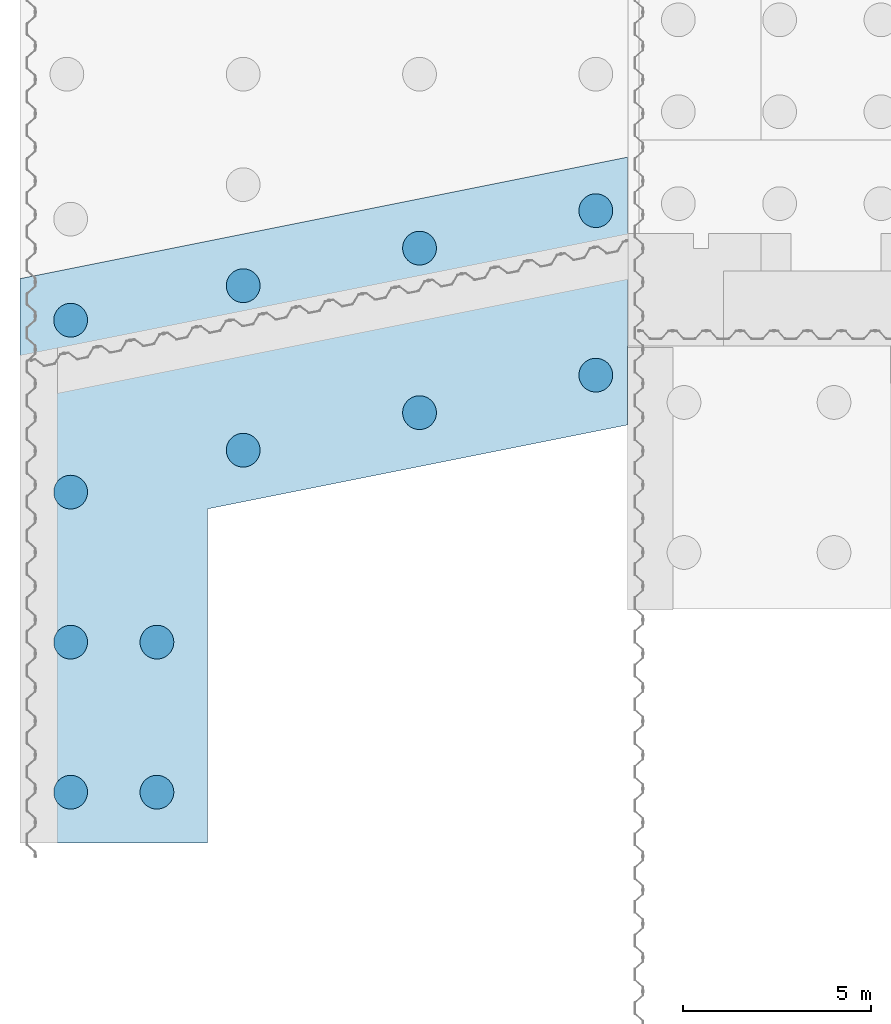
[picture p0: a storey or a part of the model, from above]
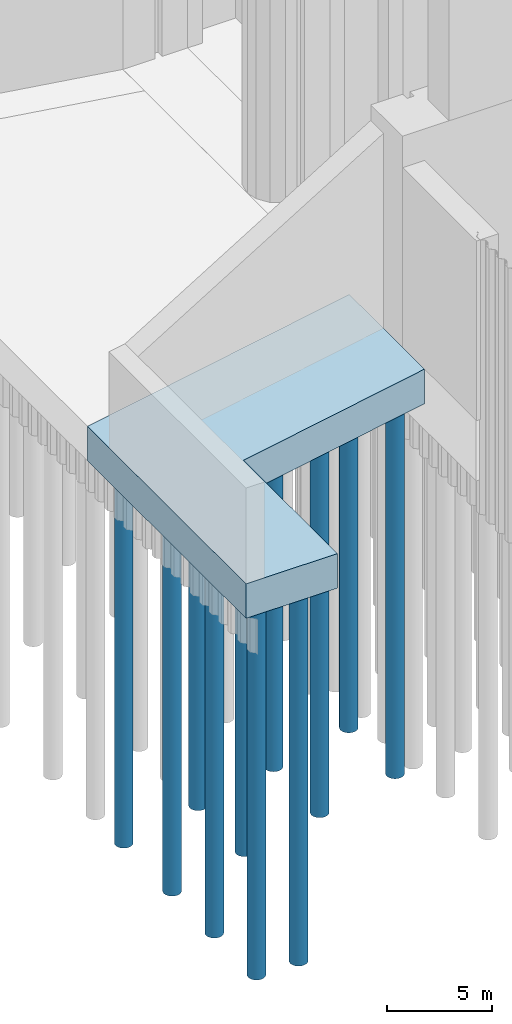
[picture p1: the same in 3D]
Properties of the parts of a building model (IFC2X3)

# File
Description: ViewDefinition [CoordinationView_V2.0]
File name: プロジェクト番号
Time: 2021-06-24T20:11:10
Written by: The EXPRESS Data Manager Version 5.02.0100.07 : 28 Aug 2013
Made in: 20210420_1515(x64) - Exporter 20.2.40.65 - 代替 UI 20.2.40.65
Comment: STEP Physical File produced by: The EXPRESS Data Manager Version 5.02.0100.07 : 28 Aug 2013 * Module: EDMstepFileFactory/EDMstandAlone * Creation date: Thu Jun 24 20:11:10 2021 * Host: A7687-TADA8 * Database: C:\Users\a9056\AppData\Local\Temp\2ef45a50-3783-4896-809c-960f0bd549e2\3312b9ed-52c4-4e0d-9066-fb21aae68b51\ifc * Database version: 5507 * Database creation date: Thu Jun 24 20:11:02 2021 * Schema: IFC2X3 * Model: DataRepository.ifc * Model creation date: Thu Jun 24 20:11:02 2021 * Header model: DataRepository.ifc_HeaderModel * Header model creation date: Thu Jun 24 20:11:02 2021 * EDMuser: sdai-user * EDMgroup: sdai-group * License ID and type: 5605 : Permanent license. Expiry date: * EDMstepFileFactory options: 020000

# IfcProject, プロジェクト番号
LongName: プロジェクト名; Phase: プロジェクト ステータス

# IfcSite, Default
RefLatitude: 35, 41, 6, 4943; RefLongitude: 139, 45, 3, 625488; RefElevation: 0 mm

# IfcBuilding
Pset_BuildingCommon - NumberOfStoreys: 1

# IfcBuildingStorey: レベル:レベル記号 - 基準, 設計GL
LongName: 設計GL; Elevation: 0 mm

# IfcSlab: 40001_Co_底版, 40001_Co_底版:40001_Co_底版:313550
In: 設計GL
Type - PredefinedType: FLOOR; Material: コンクリート - 現場打ちコンクリート
Type - Pset_QuantityTakeOff - Reference: 40001_Co_底版
Type - Pset_ReinforcementBarPitchOfSlab - Reference: 40001_Co_底版
Type - Pset_SlabCommon - Reference: 40001_Co_底版; IsExternal: no
Pset_QuantityTakeOff - sets with these values: 2
Pset_SlabCommon - PitchAngle: 0 deg

# IfcSlab: 40101_Co_川表胸壁(下流)底版, 40101_Co_川表胸壁(下流)底版:40101_Co_川表胸壁(下流)底版:313560
In: 設計GL
Type - PredefinedType: FLOOR; Material: コンクリート - 現場打ちコンクリート
Type - Pset_QuantityTakeOff - Reference: 40101_Co_川表胸壁(下流)底版
Type - Pset_ReinforcementBarPitchOfSlab - Reference: 40101_Co_川表胸壁(下流)底版
Type - Pset_SlabCommon - IsExternal: no; Reference: 40101_Co_川表胸壁(下流)底版
Pset_QuantityTakeOff - sets with these values: 2
Pset_SlabCommon - PitchAngle: 0 deg

# IfcSlab: 40201_Co_川表胸壁(上流)底版, 40201_Co_川表胸壁(上流)底版:40201_Co_川表胸壁(上流)底版:332443
In: 設計GL
Type - PredefinedType: FLOOR; Material: コンクリート - 現場打ちコンクリート
Type - Pset_QuantityTakeOff - Reference: 40201_Co_川表胸壁(上流)底版
Type - Pset_ReinforcementBarPitchOfSlab - Reference: 40201_Co_川表胸壁(上流)底版
Type - Pset_SlabCommon - IsExternal: no; Reference: 40201_Co_川表胸壁(上流)底版
Pset_QuantityTakeOff - sets with these values: 2
Pset_SlabCommon - PitchAngle: 0 deg

# IfcSlab: 40301_Co_川裏胸壁(下流)底版, 40301_Co_川裏胸壁(下流)底版:40301_Co_川裏胸壁(下流)底版:332453
In: 設計GL
Type - PredefinedType: FLOOR; Material: コンクリート - 現場打ちコンクリート
Type - Pset_QuantityTakeOff - Reference: 40301_Co_川裏胸壁(下流)底版
Type - Pset_ReinforcementBarPitchOfSlab - Reference: 40301_Co_川裏胸壁(下流)底版
Type - Pset_SlabCommon - IsExternal: no; Reference: 40301_Co_川裏胸壁(下流)底版
Pset_QuantityTakeOff - sets with these values: 2
Pset_SlabCommon - PitchAngle: 0 deg

# IfcSlab: 40401_Co_川裏胸壁(上流)底版, 40401_Co_川裏胸壁(上流)底版:40401_Co_川裏胸壁(上流)底版:332463
In: 設計GL
Type - PredefinedType: FLOOR; Material: コンクリート - 現場打ちコンクリート
Type - Pset_QuantityTakeOff - Reference: 40401_Co_川裏胸壁(上流)底版
Type - Pset_ReinforcementBarPitchOfSlab - Reference: 40401_Co_川裏胸壁(上流)底版
Type - Pset_SlabCommon - IsExternal: no; Reference: 40401_Co_川裏胸壁(上流)底版
Pset_QuantityTakeOff - sets with these values: 2
Pset_SlabCommon - PitchAngle: 0 deg

# IfcSlab: 40501_Co_川表翼壁(下流)底版, 40501_Co_川表翼壁(下流)底版:40501_Co_川表翼壁(下流)底版:332473
In: 設計GL
Type - PredefinedType: FLOOR; Material: コンクリート - 現場打ちコンクリート
Type - Pset_QuantityTakeOff - Reference: 40501_Co_川表翼壁(下流)底版
Type - Pset_ReinforcementBarPitchOfSlab - Reference: 40501_Co_川表翼壁(下流)底版
Type - Pset_SlabCommon - IsExternal: no; Reference: 40501_Co_川表翼壁(下流)底版
Pset_QuantityTakeOff - sets with these values: 2
Pset_SlabCommon - PitchAngle: 0 deg

# IfcSlab: 40601_Co_川表翼壁(上流)底版, 40601_Co_川表翼壁(上流)底版:40601_Co_川表翼壁(上流)底版:332483
In: 設計GL
Type - PredefinedType: FLOOR; Material: コンクリート - 現場打ちコンクリート
Type - Pset_QuantityTakeOff - Reference: 40601_Co_川表翼壁(上流)底版
Type - Pset_ReinforcementBarPitchOfSlab - Reference: 40601_Co_川表翼壁(上流)底版
Type - Pset_SlabCommon - IsExternal: no; Reference: 40601_Co_川表翼壁(上流)底版
Pset_QuantityTakeOff - sets with these values: 2
Pset_SlabCommon - PitchAngle: 0 deg

# IfcSlab: 40701_Co_川裏翼壁(下流)底版, 40701_Co_川裏翼壁(下流)底版:40701_Co_川裏翼壁(下流)底版:332493
In: 設計GL
Type - PredefinedType: FLOOR; Material: コンクリート - 現場打ちコンクリート
Type - Pset_QuantityTakeOff - Reference: 40701_Co_川裏翼壁(下流)底版
Type - Pset_ReinforcementBarPitchOfSlab - Reference: 40701_Co_川裏翼壁(下流)底版
Type - Pset_SlabCommon - IsExternal: no; Reference: 40701_Co_川裏翼壁(下流)底版
Pset_QuantityTakeOff - sets with these values: 2
Pset_SlabCommon - PitchAngle: 0 deg

# IfcSlab: 40801_Co_川裏翼壁(上流)底版 (3)
In: 設計GL
Type - PredefinedType: FLOOR; Material: コンクリート - 現場打ちコンクリート
Type - Pset_QuantityTakeOff - Reference: 40801_Co_川裏翼壁(上流)底版
Type - Pset_ReinforcementBarPitchOfSlab - Reference: 40801_Co_川裏翼壁(上流)底版
Type - Pset_SlabCommon - IsExternal: no; Reference: 40801_Co_川裏翼壁(上流)底版
Pset_QuantityTakeOff - sets with these values: 2
Pset_SlabCommon - PitchAngle: 0 deg
Name (40801_Co_川裏翼壁(上流)底版:40801_Co_川裏翼壁(上流)底版:...)
332503
332782
333462

# IfcSlab: 40901_Co_川表翼壁_底版, 40901_Co_川表翼壁_底版:40901_Co_川表翼壁_底版:332513
In: 設計GL
Type - PredefinedType: FLOOR; Material: コンクリート - 現場打ちコンクリート
Type - Pset_QuantityTakeOff - Reference: 40901_Co_川表翼壁_底版
Type - Pset_ReinforcementBarPitchOfSlab - Reference: 40901_Co_川表翼壁_底版
Type - Pset_SlabCommon - IsExternal: no; Reference: 40901_Co_川表翼壁_底版
Pset_QuantityTakeOff - sets with these values: 2
Pset_SlabCommon - PitchAngle: 0 deg

# IfcSlab: 41001_Co_川裏翼壁_底版, 41001_Co_川裏翼壁_底版:41001_Co_川裏翼壁_底版:332523
In: 設計GL
Type - PredefinedType: FLOOR; Material: コンクリート - 現場打ちコンクリート
Type - Pset_QuantityTakeOff - Reference: 41001_Co_川裏翼壁_底版
Type - Pset_ReinforcementBarPitchOfSlab - Reference: 41001_Co_川裏翼壁_底版
Type - Pset_SlabCommon - IsExternal: no; Reference: 41001_Co_川裏翼壁_底版
Pset_QuantityTakeOff - sets with these values: 2
Pset_SlabCommon - PitchAngle: 0 deg

# IfcSlab: 41101_Co_端堰柱(下流), 41101_Co_端堰柱(下流):41101_Co_端堰柱(下流):332533
In: 設計GL
Type - PredefinedType: FLOOR; Material: コンクリート - 現場打ちコンクリート
Type - Pset_QuantityTakeOff - Reference: 41101_Co_端堰柱(下流)
Type - Pset_ReinforcementBarPitchOfSlab - Reference: 41101_Co_端堰柱(下流)
Type - Pset_SlabCommon - IsExternal: no; Reference: 41101_Co_端堰柱(下流)
Pset_QuantityTakeOff - sets with these values: 2
Pset_SlabCommon - PitchAngle: 0 deg

# IfcSlab: 41201_Co_中央堰柱, 41201_Co_中央堰柱:41201_Co_中央堰柱:332543
In: 設計GL
Type - PredefinedType: FLOOR; Material: コンクリート - 現場打ちコンクリート
Type - Pset_QuantityTakeOff - Reference: 41201_Co_中央堰柱
Type - Pset_ReinforcementBarPitchOfSlab - Reference: 41201_Co_中央堰柱
Type - Pset_SlabCommon - IsExternal: no; Reference: 41201_Co_中央堰柱
Pset_QuantityTakeOff - sets with these values: 2
Pset_SlabCommon - PitchAngle: 0 deg

# IfcSlab: 41301_Co_端堰柱(上流), 41301_Co_端堰柱(上流):41301_Co_端堰柱(上流):332553
In: 設計GL
Type - PredefinedType: FLOOR; Material: コンクリート - 現場打ちコンクリート
Type - Pset_QuantityTakeOff - Reference: 41301_Co_端堰柱(上流)
Type - Pset_ReinforcementBarPitchOfSlab - Reference: 41301_Co_端堰柱(上流)
Type - Pset_SlabCommon - IsExternal: no; Reference: 41301_Co_端堰柱(上流)
Pset_QuantityTakeOff - sets with these values: 2
Pset_SlabCommon - PitchAngle: 0 deg

# IfcSlab: 41401_Co_川表胸壁(下流)側壁, 41401_Co_川表胸壁(下流)側壁:41401_Co_川表胸壁(下流)側壁:332563
In: 設計GL
Type - PredefinedType: FLOOR; Material: コンクリート - 現場打ちコンクリート
Type - Pset_QuantityTakeOff - Reference: 41401_Co_川表胸壁(下流)側壁
Type - Pset_ReinforcementBarPitchOfSlab - Reference: 41401_Co_川表胸壁(下流)側壁
Type - Pset_SlabCommon - IsExternal: no; Reference: 41401_Co_川表胸壁(下流)側壁
Pset_QuantityTakeOff - sets with these values: 2
Pset_SlabCommon - PitchAngle: 0 deg

# IfcSlab: 41501_Co_川表胸壁(上流)側壁, 41501_Co_川表胸壁(上流)側壁:41501_Co_川表胸壁(上流)側壁:332573
In: 設計GL
Type - PredefinedType: FLOOR; Material: コンクリート - 現場打ちコンクリート
Type - Pset_QuantityTakeOff - Reference: 41501_Co_川表胸壁(上流)側壁
Type - Pset_ReinforcementBarPitchOfSlab - Reference: 41501_Co_川表胸壁(上流)側壁
Type - Pset_SlabCommon - IsExternal: no; Reference: 41501_Co_川表胸壁(上流)側壁
Pset_QuantityTakeOff - sets with these values: 2
Pset_SlabCommon - PitchAngle: 0 deg

# IfcSlab: 41601_Co_川裏胸壁(下流)側壁, 41601_Co_川裏胸壁(下流)側壁:41601_Co_川裏胸壁(下流)側壁:332583
In: 設計GL
Type - PredefinedType: FLOOR; Material: コンクリート - 現場打ちコンクリート
Type - Pset_QuantityTakeOff - Reference: 41601_Co_川裏胸壁(下流)側壁
Type - Pset_ReinforcementBarPitchOfSlab - Reference: 41601_Co_川裏胸壁(下流)側壁
Type - Pset_SlabCommon - IsExternal: no; Reference: 41601_Co_川裏胸壁(下流)側壁
Pset_QuantityTakeOff - sets with these values: 2
Pset_SlabCommon - PitchAngle: 0 deg

# IfcSlab: 41701_Co_川裏胸壁(上流)側壁, 41701_Co_川裏胸壁(上流)側壁:41701_Co_川裏胸壁(上流)側壁:332593
In: 設計GL
Type - PredefinedType: FLOOR; Material: コンクリート - 現場打ちコンクリート
Type - Pset_QuantityTakeOff - Reference: 41701_Co_川裏胸壁(上流)側壁
Type - Pset_ReinforcementBarPitchOfSlab - Reference: 41701_Co_川裏胸壁(上流)側壁
Type - Pset_SlabCommon - IsExternal: no; Reference: 41701_Co_川裏胸壁(上流)側壁
Pset_QuantityTakeOff - sets with these values: 2
Pset_SlabCommon - PitchAngle: 0 deg

# IfcSlab: 41801_Co_川表翼壁(下流)側壁, 41801_Co_川表翼壁(下流)側壁:41801_Co_川表翼壁(下流)側壁:332603
In: 設計GL
Type - PredefinedType: FLOOR; Material: コンクリート - 現場打ちコンクリート
Type - Pset_QuantityTakeOff - Reference: 41801_Co_川表翼壁(下流)側壁
Type - Pset_ReinforcementBarPitchOfSlab - Reference: 41801_Co_川表翼壁(下流)側壁
Type - Pset_SlabCommon - IsExternal: no; Reference: 41801_Co_川表翼壁(下流)側壁
Pset_QuantityTakeOff - sets with these values: 2
Pset_SlabCommon - PitchAngle: 0 deg

# IfcSlab: 41901_Co_川表翼壁(上流)側壁, 41901_Co_川表翼壁(上流)側壁:41901_Co_川表翼壁(上流)側壁:332613
In: 設計GL
Type - PredefinedType: FLOOR; Material: コンクリート - 現場打ちコンクリート
Type - Pset_QuantityTakeOff - Reference: 41901_Co_川表翼壁(上流)側壁
Type - Pset_ReinforcementBarPitchOfSlab - Reference: 41901_Co_川表翼壁(上流)側壁
Type - Pset_SlabCommon - IsExternal: no; Reference: 41901_Co_川表翼壁(上流)側壁
Pset_QuantityTakeOff - sets with these values: 2
Pset_SlabCommon - PitchAngle: 0 deg

# IfcSlab: 42001_Co_川裏翼壁(下流)側壁, 42001_Co_川裏翼壁(下流)側壁:42001_Co_川裏翼壁(下流)側壁:332623
In: 設計GL
Type - PredefinedType: FLOOR; Material: コンクリート - 現場打ちコンクリート
Type - Pset_QuantityTakeOff - Reference: 42001_Co_川裏翼壁(下流)側壁
Type - Pset_ReinforcementBarPitchOfSlab - Reference: 42001_Co_川裏翼壁(下流)側壁
Type - Pset_SlabCommon - IsExternal: no; Reference: 42001_Co_川裏翼壁(下流)側壁
Pset_QuantityTakeOff - sets with these values: 2
Pset_SlabCommon - PitchAngle: 0 deg

# IfcSlab: 42101_Co_川裏翼壁(上流)側壁 (2)
In: 設計GL
Type - PredefinedType: FLOOR; Material: コンクリート - 現場打ちコンクリート
Type - Pset_QuantityTakeOff - Reference: 42101_Co_川裏翼壁(上流)側壁
Type - Pset_ReinforcementBarPitchOfSlab - Reference: 42101_Co_川裏翼壁(上流)側壁
Type - Pset_SlabCommon - IsExternal: no; Reference: 42101_Co_川裏翼壁(上流)側壁
Pset_QuantityTakeOff - sets with these values: 2
Pset_SlabCommon - PitchAngle: 0 deg
Name (42101_Co_川裏翼壁(上流)側壁:42101_Co_川裏翼壁(上流)側壁:...)
332633
436674

# IfcSlab: 42201_Co_端門柱(下流), 42201_Co_端門柱(下流):42201_Co_端門柱(下流):412043
In: 設計GL
Type - PredefinedType: FLOOR; Material: コンクリート - 現場打ちコンクリート
Type - Pset_QuantityTakeOff - Reference: 42201_Co_端門柱(下流)
Type - Pset_ReinforcementBarPitchOfSlab - Reference: 42201_Co_端門柱(下流)
Type - Pset_SlabCommon - IsExternal: no; Reference: 42201_Co_端門柱(下流)
Pset_QuantityTakeOff - sets with these values: 2
Pset_SlabCommon - PitchAngle: 0 deg

# IfcSlab: 42301_Co_中央門柱, 42301_Co_中央門柱:42301_Co_中央門柱:412053
In: 設計GL
Type - PredefinedType: FLOOR; Material: コンクリート - 現場打ちコンクリート
Type - Pset_QuantityTakeOff - Reference: 42301_Co_中央門柱
Type - Pset_ReinforcementBarPitchOfSlab - Reference: 42301_Co_中央門柱
Type - Pset_SlabCommon - IsExternal: no; Reference: 42301_Co_中央門柱
Pset_QuantityTakeOff - sets with these values: 2
Pset_SlabCommon - PitchAngle: 0 deg

# IfcSlab: 42401_Co_端門柱(上流), 42401_Co_端門柱(上流):42401_Co_端門柱(上流):412063
In: 設計GL
Type - PredefinedType: FLOOR; Material: コンクリート - 現場打ちコンクリート
Type - Pset_QuantityTakeOff - Reference: 42401_Co_端門柱(上流)
Type - Pset_ReinforcementBarPitchOfSlab - Reference: 42401_Co_端門柱(上流)
Type - Pset_SlabCommon - IsExternal: no; Reference: 42401_Co_端門柱(上流)
Pset_QuantityTakeOff - sets with these values: 2
Pset_SlabCommon - PitchAngle: 0 deg

# IfcSlab: 42501_Co_操作台, 42501_Co_操作台:42501_Co_操作台:412073
In: 設計GL
Type - PredefinedType: FLOOR; Material: コンクリート - 現場打ちコンクリート
Type - Pset_QuantityTakeOff - Reference: 42501_Co_操作台
Type - Pset_ReinforcementBarPitchOfSlab - Reference: 42501_Co_操作台
Type - Pset_SlabCommon - IsExternal: no; Reference: 42501_Co_操作台
Pset_QuantityTakeOff - sets with these values: 2
Pset_SlabCommon - PitchAngle: 0 deg

# IfcSlab: 50001_2次Co_底版, 50001_2次Co_底版:50001_2次Co_底版:332683
In: 設計GL
Type - PredefinedType: FLOOR; Material: コンクリート - 現場打ちコンクリート
Type - Pset_QuantityTakeOff - Reference: 50001_2次Co_底版
Type - Pset_ReinforcementBarPitchOfSlab - Reference: 50001_2次Co_底版
Type - Pset_SlabCommon - IsExternal: no; Reference: 50001_2次Co_底版
Pset_QuantityTakeOff - sets with these values: 2
Pset_SlabCommon - PitchAngle: 0 deg

# IfcSlab: 51101_2次Co_端堰柱(下流), 51101_2次Co_端堰柱(下流):51101_2次Co_端堰柱(下流):332693
In: 設計GL
Type - PredefinedType: FLOOR; Material: コンクリート - 現場打ちコンクリート
Type - Pset_QuantityTakeOff - Reference: 51101_2次Co_端堰柱(下流)
Type - Pset_ReinforcementBarPitchOfSlab - Reference: 51101_2次Co_端堰柱(下流)
Type - Pset_SlabCommon - IsExternal: no; Reference: 51101_2次Co_端堰柱(下流)
Pset_QuantityTakeOff - sets with these values: 2
Pset_SlabCommon - PitchAngle: 0 deg

# IfcSlab: 51201_2次Co_中央堰柱, 51201_2次Co_中央堰柱:51201_2次Co_中央堰柱:332703
In: 設計GL
Type - PredefinedType: FLOOR; Material: コンクリート - 現場打ちコンクリート
Type - Pset_QuantityTakeOff - Reference: 51201_2次Co_中央堰柱
Type - Pset_ReinforcementBarPitchOfSlab - Reference: 51201_2次Co_中央堰柱
Type - Pset_SlabCommon - IsExternal: no; Reference: 51201_2次Co_中央堰柱
Pset_QuantityTakeOff - sets with these values: 2
Pset_SlabCommon - PitchAngle: 0 deg

# IfcSlab: 51301_2次Co_端堰柱(上流), 51301_2次Co_端堰柱(上流):51301_2次Co_端堰柱(上流):334153
In: 設計GL
Type - PredefinedType: FLOOR; Material: コンクリート - 現場打ちコンクリート
Type - Pset_QuantityTakeOff - Reference: 51301_2次Co_端堰柱(上流)
Type - Pset_ReinforcementBarPitchOfSlab - Reference: 51301_2次Co_端堰柱(上流)
Type - Pset_SlabCommon - IsExternal: no; Reference: 51301_2次Co_端堰柱(上流)
Pset_QuantityTakeOff - sets with these values: 2
Pset_SlabCommon - PitchAngle: 0 deg

# IfcSlab: 60301_Co_操作台(下流), 60301_Co_操作台(下流):60301_Co_操作台(下流):412033
In: 設計GL
Type - PredefinedType: FLOOR; Material: コンクリート - 現場打ちコンクリート
Type - Pset_QuantityTakeOff - Reference: 60301_Co_操作台(下流)
Type - Pset_ReinforcementBarPitchOfSlab - Reference: 60301_Co_操作台(下流)
Type - Pset_SlabCommon - IsExternal: no; Reference: 60301_Co_操作台(下流)
Pset_QuantityTakeOff - sets with these values: 2
Pset_SlabCommon - PitchAngle: 0 deg

# IfcSlab: 60401_Co_操作台(中央), 60401_Co_操作台(中央):60401_Co_操作台(中央):412013
In: 設計GL
Type - PredefinedType: FLOOR; Material: コンクリート - 現場打ちコンクリート
Type - Pset_QuantityTakeOff - Reference: 60401_Co_操作台(中央)
Type - Pset_ReinforcementBarPitchOfSlab - Reference: 60401_Co_操作台(中央)
Type - Pset_SlabCommon - IsExternal: no; Reference: 60401_Co_操作台(中央)
Pset_QuantityTakeOff - sets with these values: 2
Pset_SlabCommon - PitchAngle: 0 deg

# IfcSlab: 60501_Co_操作台(上流), 60501_Co_操作台(上流):60501_Co_操作台(上流):412023
In: 設計GL
Type - PredefinedType: FLOOR; Material: コンクリート - 現場打ちコンクリート
Type - Pset_QuantityTakeOff - Reference: 60501_Co_操作台(上流)
Type - Pset_ReinforcementBarPitchOfSlab - Reference: 60501_Co_操作台(上流)
Type - Pset_SlabCommon - IsExternal: no; Reference: 60501_Co_操作台(上流)
Pset_QuantityTakeOff - sets with these values: 2
Pset_SlabCommon - PitchAngle: 0 deg

# IfcSlab: 60601_操作室, 60601_操作室:60601_操作室:436539
In: 設計GL
Type - PredefinedType: FLOOR; Material: コンクリート - 現場打ちコンクリート
Type - Pset_QuantityTakeOff - Reference: 60601_操作室
Type - Pset_ReinforcementBarPitchOfSlab - Reference: 60601_操作室
Type - Pset_SlabCommon - IsExternal: no; Reference: 60601_操作室
Pset_QuantityTakeOff - sets with these values: 2
Pset_SlabCommon - PitchAngle: 0 deg

# IfcSlab: 70001.dwg, 70001.dwg:70001.dwg:412083
In: 設計GL
Type - PredefinedType: FLOOR; Material: ベタ基礎
Type - Pset_QuantityTakeOff - Reference: 70001.dwg
Type - Pset_ReinforcementBarPitchOfSlab - Reference: 70001.dwg
Type - Pset_SlabCommon - IsExternal: no; Reference: 70001.dwg
Pset_QuantityTakeOff - sets with these values: 2
Pset_SlabCommon - PitchAngle: 0 deg

# IfcSlab: 70101.dwg, 70101.dwg:70101.dwg:436809
In: 設計GL
Type - PredefinedType: FLOOR; Material: ベタ基礎
Type - Pset_QuantityTakeOff - Reference: 70101.dwg
Type - Pset_ReinforcementBarPitchOfSlab - Reference: 70101.dwg
Type - Pset_SlabCommon - IsExternal: no; Reference: 70101.dwg
Pset_QuantityTakeOff - sets with these values: 2
Pset_SlabCommon - PitchAngle: 0 deg

# IfcSlab: 70201.dwg, 70201.dwg:70201.dwg:412103
In: 設計GL
Type - PredefinedType: FLOOR; Material: ベタ基礎
Type - Pset_QuantityTakeOff - Reference: 70201.dwg
Type - Pset_ReinforcementBarPitchOfSlab - Reference: 70201.dwg
Type - Pset_SlabCommon - IsExternal: no; Reference: 70201.dwg
Pset_QuantityTakeOff - sets with these values: 2
Pset_SlabCommon - PitchAngle: 0 deg

# IfcSlab: 70301.dwg, 70301.dwg:70301.dwg:412113
In: 設計GL
Type - PredefinedType: FLOOR; Material: ベタ基礎
Type - Pset_QuantityTakeOff - Reference: 70301.dwg
Type - Pset_ReinforcementBarPitchOfSlab - Reference: 70301.dwg
Type - Pset_SlabCommon - IsExternal: no; Reference: 70301.dwg
Pset_QuantityTakeOff - sets with these values: 2
Pset_SlabCommon - PitchAngle: 0 deg

# IfcSlab: 70401.dwg, 70401.dwg:70401.dwg:412123
In: 設計GL
Type - PredefinedType: FLOOR; Material: ベタ基礎
Type - Pset_QuantityTakeOff - Reference: 70401.dwg
Type - Pset_ReinforcementBarPitchOfSlab - Reference: 70401.dwg
Type - Pset_SlabCommon - IsExternal: no; Reference: 70401.dwg
Pset_QuantityTakeOff - sets with these values: 2
Pset_SlabCommon - PitchAngle: 0 deg

# IfcSlab: 70501.dwg, 70501.dwg:70501.dwg:412133
In: 設計GL
Type - PredefinedType: FLOOR; Material: ベタ基礎
Type - Pset_QuantityTakeOff - Reference: 70501.dwg
Type - Pset_ReinforcementBarPitchOfSlab - Reference: 70501.dwg
Type - Pset_SlabCommon - IsExternal: no; Reference: 70501.dwg
Pset_QuantityTakeOff - sets with these values: 2
Pset_SlabCommon - PitchAngle: 0 deg

# IfcSlab: 70601.dwg, 70601.dwg:70601.dwg:414341
In: 設計GL
Type - PredefinedType: FLOOR; Material: ベタ基礎
Type - Pset_QuantityTakeOff - Reference: 70601.dwg
Type - Pset_ReinforcementBarPitchOfSlab - Reference: 70601.dwg
Type - Pset_SlabCommon - IsExternal: no; Reference: 70601.dwg
Pset_QuantityTakeOff - sets with these values: 2
Pset_SlabCommon - PitchAngle: 0 deg

# IfcSlab: 70701.dwg, 70701.dwg:70701.dwg:412153
In: 設計GL
Type - PredefinedType: FLOOR; Material: ベタ基礎
Type - Pset_QuantityTakeOff - Reference: 70701.dwg
Type - Pset_ReinforcementBarPitchOfSlab - Reference: 70701.dwg
Type - Pset_SlabCommon - IsExternal: no; Reference: 70701.dwg
Pset_QuantityTakeOff - sets with these values: 2
Pset_SlabCommon - PitchAngle: 0 deg

# IfcSlab: 70801.dwg, 70801.dwg:70801.dwg:412163
In: 設計GL
Type - PredefinedType: FLOOR; Material: ベタ基礎
Type - Pset_QuantityTakeOff - Reference: 70801.dwg
Type - Pset_ReinforcementBarPitchOfSlab - Reference: 70801.dwg
Type - Pset_SlabCommon - IsExternal: no; Reference: 70801.dwg
Pset_QuantityTakeOff - sets with these values: 2
Pset_SlabCommon - PitchAngle: 0 deg

# IfcSlab: 70901.dwg, 70901.dwg:70901.dwg:412979
In: 設計GL
Type - PredefinedType: FLOOR; Material: ベタ基礎
Type - Pset_QuantityTakeOff - Reference: 70901.dwg
Type - Pset_ReinforcementBarPitchOfSlab - Reference: 70901.dwg
Type - Pset_SlabCommon - IsExternal: no; Reference: 70901.dwg
Pset_QuantityTakeOff - sets with these values: 2
Pset_SlabCommon - PitchAngle: 0 deg

# IfcSlab: 71001.dwg, 71001.dwg:71001.dwg:412183
In: 設計GL
Type - PredefinedType: FLOOR; Material: ベタ基礎
Type - Pset_QuantityTakeOff - Reference: 71001.dwg
Type - Pset_ReinforcementBarPitchOfSlab - Reference: 71001.dwg
Type - Pset_SlabCommon - IsExternal: no; Reference: 71001.dwg
Pset_QuantityTakeOff - sets with these values: 2
Pset_SlabCommon - PitchAngle: 0 deg

# IfcSlab: 80001.dwg, 80001.dwg:80001.dwg:412193
In: 設計GL
Type - PredefinedType: FLOOR; Material: ガラス
Type - Pset_QuantityTakeOff - Reference: 80001.dwg
Type - Pset_ReinforcementBarPitchOfSlab - Reference: 80001.dwg
Type - Pset_SlabCommon - IsExternal: no; Reference: 80001.dwg
Pset_QuantityTakeOff - sets with these values: 2
Pset_SlabCommon - PitchAngle: 0 deg

# IfcSlab: 80101.dwg, 80101.dwg:80101.dwg:412208
In: 設計GL
Type - PredefinedType: FLOOR; Material: ガラス
Type - Pset_QuantityTakeOff - Reference: 80101.dwg
Type - Pset_ReinforcementBarPitchOfSlab - Reference: 80101.dwg
Type - Pset_SlabCommon - IsExternal: no; Reference: 80101.dwg
Pset_QuantityTakeOff - sets with these values: 2
Pset_SlabCommon - PitchAngle: 0 deg

# IfcSlab: 80201.dwg, 80201.dwg:80201.dwg:412298
In: 設計GL
Type - PredefinedType: FLOOR; Material: ガラス
Type - Pset_QuantityTakeOff - Reference: 80201.dwg
Type - Pset_ReinforcementBarPitchOfSlab - Reference: 80201.dwg
Type - Pset_SlabCommon - IsExternal: no; Reference: 80201.dwg
Pset_QuantityTakeOff - sets with these values: 2
Pset_SlabCommon - PitchAngle: 0 deg

# IfcSlab: 80301.dwg, 80301.dwg:80301.dwg:412218
In: 設計GL
Type - PredefinedType: FLOOR; Material: ガラス
Type - Pset_QuantityTakeOff - Reference: 80301.dwg
Type - Pset_ReinforcementBarPitchOfSlab - Reference: 80301.dwg
Type - Pset_SlabCommon - IsExternal: no; Reference: 80301.dwg
Pset_QuantityTakeOff - sets with these values: 2
Pset_SlabCommon - PitchAngle: 0 deg

# IfcSlab: 80401.dwg, 80401.dwg:80401.dwg:412228
In: 設計GL
Type - PredefinedType: FLOOR; Material: ガラス
Type - Pset_QuantityTakeOff - Reference: 80401.dwg
Type - Pset_ReinforcementBarPitchOfSlab - Reference: 80401.dwg
Type - Pset_SlabCommon - IsExternal: no; Reference: 80401.dwg
Pset_QuantityTakeOff - sets with these values: 2
Pset_SlabCommon - PitchAngle: 0 deg

# IfcSlab: 80501.dwg, 80501.dwg:80501.dwg:412238
In: 設計GL
Type - PredefinedType: FLOOR; Material: ガラス
Type - Pset_QuantityTakeOff - Reference: 80501.dwg
Type - Pset_ReinforcementBarPitchOfSlab - Reference: 80501.dwg
Type - Pset_SlabCommon - IsExternal: no; Reference: 80501.dwg
Pset_QuantityTakeOff - sets with these values: 2
Pset_SlabCommon - PitchAngle: 0 deg

# IfcSlab: 80601.dwg, 80601.dwg:80601.dwg:412248
In: 設計GL
Type - PredefinedType: FLOOR; Material: ガラス
Type - Pset_QuantityTakeOff - Reference: 80601.dwg
Type - Pset_ReinforcementBarPitchOfSlab - Reference: 80601.dwg
Type - Pset_SlabCommon - IsExternal: no; Reference: 80601.dwg
Pset_QuantityTakeOff - sets with these values: 2
Pset_SlabCommon - PitchAngle: 0 deg

# IfcSlab: 80701.dwg, 80701.dwg:80701.dwg:412258
In: 設計GL
Type - PredefinedType: FLOOR; Material: ガラス
Type - Pset_QuantityTakeOff - Reference: 80701.dwg
Type - Pset_ReinforcementBarPitchOfSlab - Reference: 80701.dwg
Type - Pset_SlabCommon - IsExternal: no; Reference: 80701.dwg
Pset_QuantityTakeOff - sets with these values: 2
Pset_SlabCommon - PitchAngle: 0 deg

# IfcSlab: 80801.dwg, 80801.dwg:80801.dwg:412268
In: 設計GL
Type - PredefinedType: FLOOR; Material: ガラス
Type - Pset_QuantityTakeOff - Reference: 80801.dwg
Type - Pset_ReinforcementBarPitchOfSlab - Reference: 80801.dwg
Type - Pset_SlabCommon - IsExternal: no; Reference: 80801.dwg
Pset_QuantityTakeOff - sets with these values: 2
Pset_SlabCommon - PitchAngle: 0 deg

# IfcSlab: 80901.dwg, 80901.dwg:80901.dwg:412278
In: 設計GL
Type - PredefinedType: FLOOR; Material: ガラス
Type - Pset_QuantityTakeOff - Reference: 80901.dwg
Type - Pset_ReinforcementBarPitchOfSlab - Reference: 80901.dwg
Type - Pset_SlabCommon - IsExternal: no; Reference: 80901.dwg
Pset_QuantityTakeOff - sets with these values: 2
Pset_SlabCommon - PitchAngle: 0 deg

# IfcSlab: 81001.dwg, 81001.dwg:81001.dwg:412288
In: 設計GL
Type - PredefinedType: FLOOR
Type - Pset_QuantityTakeOff - Reference: 81001.dwg
Type - Pset_ReinforcementBarPitchOfSlab - Reference: 81001.dwg
Type - Pset_SlabCommon - IsExternal: no; Reference: 81001.dwg
Pset_QuantityTakeOff - sets with these values: 2
Pset_SlabCommon - PitchAngle: 0 deg
